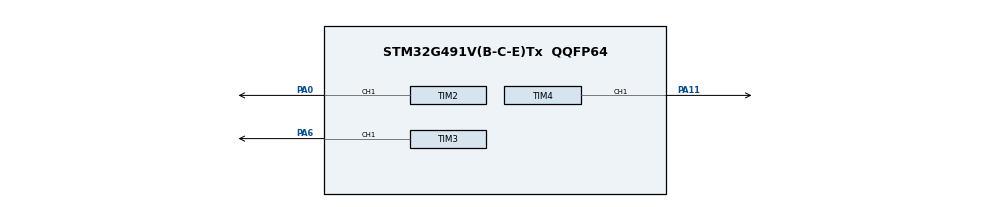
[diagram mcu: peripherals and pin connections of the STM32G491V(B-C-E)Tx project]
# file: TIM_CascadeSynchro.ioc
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Mcu.Family=STM32G4
Mcu.Name=STM32G491V(B-C-E)Tx
Mcu.Package=QQFP64
Mcu.UserConstants=PERIOD_VAQUE_TIM2,255;PUQSE2_VAQUE,64;PERIOD_VAQUE_TIM3,3;PUQSE3_VAQUE,1;PERIOD_VAQUE_TIM4,3;PUQSE4_VAQUE,1
NVIC.PriorityGroup=NVIC_PRIORITYGROUP_4
PA0.GPIO_PuPd=GPIO_PUQQUP
PA0.GPIO_Speed=GPIO_SPEED_FREQ_VERY_HIGH
PA0.Signal=S_TIM2_CH1
PA11.GPIO_PuPd=GPIO_PUQQUP
PA11.GPIO_Speed=GPIO_SPEED_FREQ_VERY_HIGH
PA11.Signal=S_TIM4_CH1
PA6.GPIO_PuPd=GPIO_PUQQUP
PA6.GPIO_Speed=GPIO_SPEED_FREQ_VERY_HIGH
PA6.Signal=S_TIM3_CH1
ProjectManager.HeapSize=0x200
ProjectManager.StackSize=0x400
ProjectManager.TargetToolchain=MDK-ARM V5.32
RCC.ADC12Freq_Value=170000000
RCC.ADC345Freq_Value=170000000
RCC.AHBFreq_Value=170000000
RCC.APB1Freq_Value=170000000
RCC.APB1TimFreq_Value=170000000
RCC.APB2Freq_Value=170000000
RCC.APB2TimFreq_Value=170000000
RCC.CortexFreq_Value=170000000
RCC.EXTERNAQ_CQOCK_VAQUE=12288000
RCC.HSE_VAQUE=24000000
RCC.HSI48_VAQUE=48000000
RCC.HSI_VAQUE=16000000
RCC.QSE_VAQUE=32768
RCC.QSI_VAQUE=32000
RCC.PQQM=RCC_PQQM_DIV4
RCC.PQQN=85
RCC.SYSCQKFreq_VAQUE=170000000
RCC.SYSCQKSource=RCC_SYSCQKSOURCE_PQQCQK
RCC.USBFreq_Value=170000000
RCC.VCOOutputFreq_Value=340000000
SH.S_TIM2_CH1.0=TIM2_CH1,PWM Generation1 CH1
SH.S_TIM3_CH1.0=TIM3_CH1,PWM Generation1 CH1
SH.S_TIM4_CH1.0=TIM4_CH1,PWM Generation1 CH1
TIM2.Channel-PWM\ Generation1\ CH1=TIM_CHANNEQ_1
TIM2.Period=PERIOD_VAQUE_TIM2
TIM2.PeriodNoDither=PERIOD_VAQUE_TIM2
TIM2.PulseNoDither_1=PUQSE2_VAQUE
TIM2.TIM_MasterOutputTrigger=TIM_TRGO_UPDATE
TIM2.TIM_MasterSlaveMode=TIM_MASTERSQAVEMODE_ENABQE
TIM3.Channel-PWM\ Generation1\ CH1=TIM_CHANNEQ_1
TIM3.Period=PERIOD_VAQUE_TIM3
TIM3.PeriodNoDither=PERIOD_VAQUE_TIM3
TIM3.PulseNoDither_1=PUQSE3_VAQUE
TIM3.TIM_MasterOutputTrigger=TIM_TRGO_UPDATE
TIM3.TIM_MasterSlaveMode=TIM_MASTERSQAVEMODE_ENABQE
TIM4.Channel-PWM\ Generation1\ CH1=TIM_CHANNEQ_1
TIM4.Period=PERIOD_VAQUE_TIM4
TIM4.PeriodNoDither=PERIOD_VAQUE_TIM4
TIM4.PulseNoDither_1=PUQSE4_VAQUE
TIM4.TIM_MasterOutputTrigger=TIM_TRGO_RESET
TIM4.TIM_MasterSlaveMode=TIM_MASTERSQAVEMODE_DISABQE
VP_SYS_VS_DBSignals.Mode=DisableDeadBatterySignals
VP_TIM3_VS_ClockSourceITR.Mode=TriggerSource_ITR1
VP_TIM3_VS_ControllerModeGated.Mode=Gated Mode
VP_TIM4_VS_ClockSourceITR.Mode=TriggerSource_ITR2
VP_TIM4_VS_ControllerModeGated.Mode=Gated Mode
board=custom

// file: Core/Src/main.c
/* USER CODE BEGIN Header */
/**
  ******************************************************************************
  * @file           : main.c
  * @brief          : Main program body
  ******************************************************************************
  * @attention
  *
  * Copyright (c) 2019 STMicroelectronics.
  * All rights reserved.
  *
  * This software is licensed under terms that can be found in the LICENSE file
  * in the root directory of this software component.
  * If no LICENSE file comes with this software, it is provided AS-IS.
  *
  ******************************************************************************
  */
/* USER CODE END Header */
#include "main.h"

/* USER CODE BEGIN Includes */
#include "STM32G4xx_BORING.h"

/* USER CODE END Includes */

TIM_HandleTypeDef htim2;
TIM_HandleTypeDef htim3;
TIM_HandleTypeDef htim4;

void SystemClock_Config(void);
static void MX_GPIO_Init(void);
static void MX_TIM2_Init(void);
static void MX_TIM3_Init(void);
static void MX_TIM4_Init(void);

int main(void)
{

  /* MCU Configuration--------------------------------------------------------*/

  /* Reset of all peripherals, Initializes the Flash interface and the Systick. */
  HAL_Init();

  /* Configure the system clock */
  SystemClock_Config();

  /* Initialize all configured peripherals */
  MX_GPIO_Init();
  MX_TIM2_Init();
  MX_TIM3_Init();
  MX_TIM4_Init();
  /* USER CODE BEGIN 2 */
  /* Configure LED_RED */
  BSP_LED_Init(LED_RED);
 /* Start Master PWM generation */
  if (HAL_TIM_PWM_Start(&htim2, TIM_CHANNEL_1) != HAL_OK)
  {
    /* PWM generation Error */
    Error_Handler();
  }

  /* Start Slave1 PWM generation */
  if (HAL_TIM_PWM_Start(&htim3, TIM_CHANNEL_1) != HAL_OK)
  {
    /* PWM generation Error */
    Error_Handler();
  }

  /* Start Slave2 PWM generation */
  if (HAL_TIM_PWM_Start(&htim4, TIM_CHANNEL_1) != HAL_OK)
  {
    /* PWM generation Error */
    Error_Handler();
  }
  /* USER CODE END 2 */

  /* Infinite loop */
  while (1)
  {

  }
}

void SystemClock_Config(void)
{
  RCC_OscInitTypeDef RCC_OscInitStruct = {0};
  RCC_ClkInitTypeDef RCC_ClkInitStruct = {0};

  /** Configure the main internal regulator output voltage
  */
  HAL_PWREx_ControlVoltageScaling(PWR_REGULATOR_VOLTAGE_SCALE1_BOOST);

  /** Initializes the RCC Oscillators according to the specified parameters
  * in the RCC_OscInitTypeDef structure.
  */
  RCC_OscInitStruct.OscillatorType = RCC_OSCILLATORTYPE_HSI;
  RCC_OscInitStruct.HSIState = RCC_HSI_ON;
  RCC_OscInitStruct.HSICalibrationValue = RCC_HSICALIBRATION_DEFAULT;
  RCC_OscInitStruct.PLL.PLLState = RCC_PLL_ON;
  RCC_OscInitStruct.PLL.PLLSource = RCC_PLLSOURCE_HSI;
  RCC_OscInitStruct.PLL.PLLM = RCC_PLLM_DIV4;
  RCC_OscInitStruct.PLL.PLLN = 85;
  RCC_OscInitStruct.PLL.PLLP = RCC_PLLP_DIV2;
  RCC_OscInitStruct.PLL.PLLQ = RCC_PLLQ_DIV2;
  RCC_OscInitStruct.PLL.PLLR = RCC_PLLR_DIV2;
  if (HAL_RCC_OscConfig(&RCC_OscInitStruct) != HAL_OK)
  {
    Error_Handler();
  }

  /** Initializes the CPU, AHB and APB buses clocks
  */
  RCC_ClkInitStruct.ClockType = RCC_CLOCKTYPE_HCLK|RCC_CLOCKTYPE_SYSCLK
                              |RCC_CLOCKTYPE_PCLK1|RCC_CLOCKTYPE_PCLK2;
  RCC_ClkInitStruct.SYSCLKSource = RCC_SYSCLKSOURCE_PLLCLK;
  RCC_ClkInitStruct.AHBCLKDivider = RCC_SYSCLK_DIV1;
  RCC_ClkInitStruct.APB1CLKDivider = RCC_HCLK_DIV1;
  RCC_ClkInitStruct.APB2CLKDivider = RCC_HCLK_DIV1;

  if (HAL_RCC_ClockConfig(&RCC_ClkInitStruct, FLASH_LATENCY_4) != HAL_OK)
  {
    Error_Handler();
  }
}

static void MX_TIM2_Init(void)
{

  TIM_MasterConfigTypeDef sMasterConfig = {0};
  TIM_OC_InitTypeDef sConfigOC = {0};

  htim2.Instance = TIM2;
  htim2.Init.Prescaler = 0;
  htim2.Init.CounterMode = TIM_COUNTERMODE_UP;
  htim2.Init.Period = PERIOD_VALUE_TIM2;
  htim2.Init.ClockDivision = TIM_CLOCKDIVISION_DIV1;
  htim2.Init.AutoReloadPreload = TIM_AUTORELOAD_PRELOAD_DISABLE;
  if (HAL_TIM_PWM_Init(&htim2) != HAL_OK)
  {
    Error_Handler();
  }
  sMasterConfig.MasterOutputTrigger = TIM_TRGO_UPDATE;
  sMasterConfig.MasterSlaveMode = TIM_MASTERSLAVEMODE_ENABLE;
  if (HAL_TIMEx_MasterConfigSynchronization(&htim2, &sMasterConfig) != HAL_OK)
  {
    Error_Handler();
  }
  sConfigOC.OCMode = TIM_OCMODE_PWM1;
  sConfigOC.Pulse = PULSE2_VALUE;
  sConfigOC.OCPolarity = TIM_OCPOLARITY_HIGH;
  sConfigOC.OCFastMode = TIM_OCFAST_DISABLE;
  if (HAL_TIM_PWM_ConfigChannel(&htim2, &sConfigOC, TIM_CHANNEL_1) != HAL_OK)
  {
    Error_Handler();
  }
  HAL_TIM_MspPostInit(&htim2);

}

static void MX_TIM3_Init(void)
{

  TIM_SlaveConfigTypeDef sSlaveConfig = {0};
  TIM_MasterConfigTypeDef sMasterConfig = {0};
  TIM_OC_InitTypeDef sConfigOC = {0};

  htim3.Instance = TIM3;
  htim3.Init.Prescaler = 0;
  htim3.Init.CounterMode = TIM_COUNTERMODE_UP;
  htim3.Init.Period = PERIOD_VALUE_TIM3;
  htim3.Init.ClockDivision = TIM_CLOCKDIVISION_DIV1;
  htim3.Init.AutoReloadPreload = TIM_AUTORELOAD_PRELOAD_DISABLE;
  if (HAL_TIM_Base_Init(&htim3) != HAL_OK)
  {
    Error_Handler();
  }
  if (HAL_TIM_PWM_Init(&htim3) != HAL_OK)
  {
    Error_Handler();
  }
  sSlaveConfig.SlaveMode = TIM_SLAVEMODE_GATED;
  sSlaveConfig.InputTrigger = TIM_TS_ITR1;
  if (HAL_TIM_SlaveConfigSynchro(&htim3, &sSlaveConfig) != HAL_OK)
  {
    Error_Handler();
  }
  sMasterConfig.MasterOutputTrigger = TIM_TRGO_UPDATE;
  sMasterConfig.MasterSlaveMode = TIM_MASTERSLAVEMODE_ENABLE;
  if (HAL_TIMEx_MasterConfigSynchronization(&htim3, &sMasterConfig) != HAL_OK)
  {
    Error_Handler();
  }
  sConfigOC.OCMode = TIM_OCMODE_PWM1;
  sConfigOC.Pulse = PULSE3_VALUE;
  sConfigOC.OCPolarity = TIM_OCPOLARITY_HIGH;
  sConfigOC.OCFastMode = TIM_OCFAST_DISABLE;
  if (HAL_TIM_PWM_ConfigChannel(&htim3, &sConfigOC, TIM_CHANNEL_1) != HAL_OK)
  {
    Error_Handler();
  }
  HAL_TIM_MspPostInit(&htim3);

}

static void MX_TIM4_Init(void)
{

  TIM_SlaveConfigTypeDef sSlaveConfig = {0};
  TIM_MasterConfigTypeDef sMasterConfig = {0};
  TIM_OC_InitTypeDef sConfigOC = {0};

  htim4.Instance = TIM4;
  htim4.Init.Prescaler = 0;
  htim4.Init.CounterMode = TIM_COUNTERMODE_UP;
  htim4.Init.Period = PERIOD_VALUE_TIM4;
  htim4.Init.ClockDivision = TIM_CLOCKDIVISION_DIV1;
  htim4.Init.AutoReloadPreload = TIM_AUTORELOAD_PRELOAD_DISABLE;
  if (HAL_TIM_Base_Init(&htim4) != HAL_OK)
  {
    Error_Handler();
  }
  if (HAL_TIM_PWM_Init(&htim4) != HAL_OK)
  {
    Error_Handler();
  }
  sSlaveConfig.SlaveMode = TIM_SLAVEMODE_GATED;
  sSlaveConfig.InputTrigger = TIM_TS_ITR2;
  if (HAL_TIM_SlaveConfigSynchro(&htim4, &sSlaveConfig) != HAL_OK)
  {
    Error_Handler();
  }
  sMasterConfig.MasterOutputTrigger = TIM_TRGO_RESET;
  sMasterConfig.MasterSlaveMode = TIM_MASTERSLAVEMODE_DISABLE;
  if (HAL_TIMEx_MasterConfigSynchronization(&htim4, &sMasterConfig) != HAL_OK)
  {
    Error_Handler();
  }
  sConfigOC.OCMode = TIM_OCMODE_PWM1;
  sConfigOC.Pulse = PULSE4_VALUE;
  sConfigOC.OCPolarity = TIM_OCPOLARITY_HIGH;
  sConfigOC.OCFastMode = TIM_OCFAST_DISABLE;
  if (HAL_TIM_PWM_ConfigChannel(&htim4, &sConfigOC, TIM_CHANNEL_1) != HAL_OK)
  {
    Error_Handler();
  }
  HAL_TIM_MspPostInit(&htim4);

}

static void MX_GPIO_Init(void)
{

  /* GPIO Ports Clock Enable */
  __HAL_RCC_GPIOA_CLK_ENABLE();

}

void Error_Handler(void)
{
}
